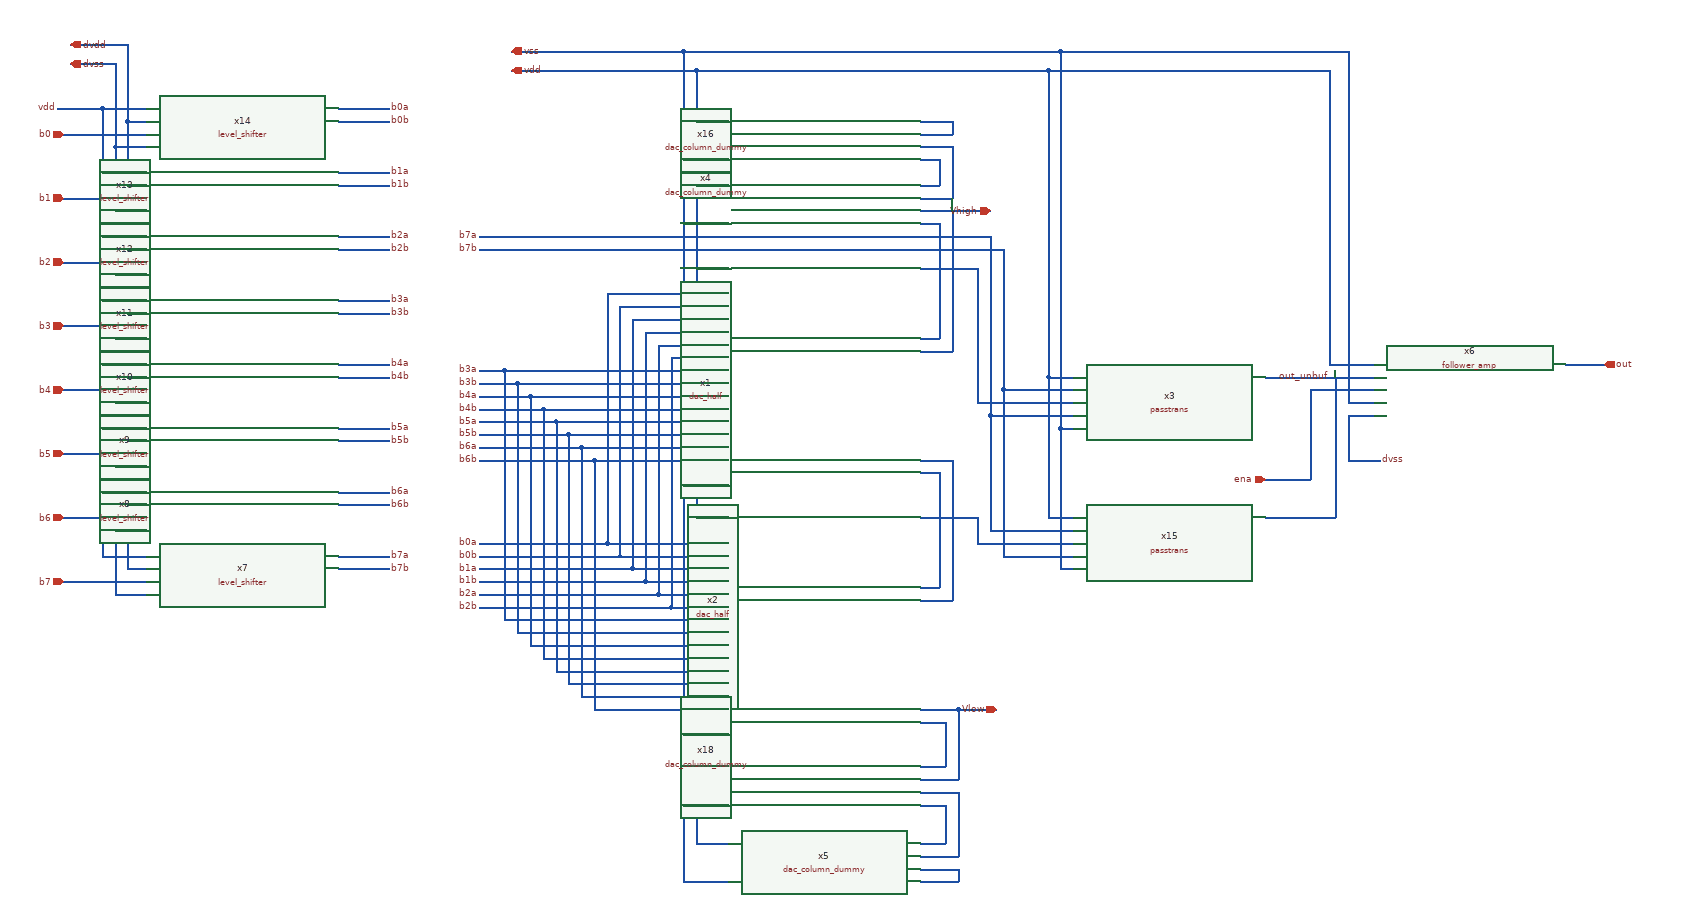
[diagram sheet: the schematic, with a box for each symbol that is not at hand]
v {xschem version=3.4.5 file_version=1.2
}
G {}
K {}
V {}
S {}
E {}
N 300 -2900 390 -2900 {
lab=#net1}
N 300 -2510 390 -2510 {
lab=#net2}
N 300 -2790 330 -2790 {
lab=#net3}
N 300 -2770 340 -2770 {
lab=Vhigh}
N 350 -2990 350 -2770 {
lab=Vhigh}
N 300 -2990 340 -2990 {
lab=Vhigh}
N 330 -2970 330 -2790 {
lab=#net3}
N 300 -2970 330 -2970 {
lab=#net3}
N 340 -2990 410 -2990 {
lab=Vhigh}
N 300 -2190 340 -2190 {
lab=#net4}
N 340 -2190 340 -2120 {
lab=#net4}
N 300 -2120 340 -2120 {
lab=#net4}
N 300 -2210 360 -2210 {
lab=Vlow}
N 360 -2210 360 -2100 {
lab=Vlow}
N 300 -2100 360 -2100 {
lab=Vlow}
N 360 -2210 420 -2210 {
lab=Vlow}
N 300 -2580 330 -2580 {
lab=#net5}
N 330 -2580 330 -2400 {
lab=#net5}
N 300 -2400 330 -2400 {
lab=#net5}
N 300 -2600 350 -2600 {
lab=#net6}
N 350 -2600 350 -2380 {
lab=#net6}
N 300 -2380 350 -2380 {
lab=#net6}
N 410 -2950 410 -2670 {
lab=b7a}
N 390 -2690 470 -2690 {
lab=#net1}
N 410 -2670 470 -2670 {
lab=b7a}
N 430 -2710 470 -2710 {
lab=b7b}
N 430 -2930 430 -2710 {
lab=b7b}
N -50 -3210 -50 -2120 {
lab=vdd}
N -340 -3240 -70 -3240 {
lab=vss}
N -70 -2560 -0 -2560 {
lab=vss}
N -70 -2170 -0 -2170 {
lab=vss}
N 470 -2710 540 -2710 {
lab=b7b}
N 470 -2690 540 -2690 {
lab=#net1}
N 470 -2670 540 -2670 {
lab=b7a}
N 520 -2650 540 -2650 {
lab=vss}
N 520 -3240 520 -2650 {
lab=vss}
N -70 -3240 520 -3240 {
lab=vss}
N -50 -3210 500 -3210 {
lab=vdd}
N 500 -3210 500 -2730 {
lab=vdd}
N 500 -2730 540 -2730 {
lab=vdd}
N -340 -3210 -50 -3210 {
lab=vdd}
N -50 -2900 -0 -2900 {
lab=vdd}
N -50 -2510 -0 -2510 {
lab=vdd}
N -90 -2370 0 -2370 {
lab=b2b}
N -110 -2390 0 -2390 {
lab=b2a}
N -130 -2410 0 -2410 {
lab=b1b}
N -150 -2430 0 -2430 {
lab=b1a}
N -170 -2450 0 -2450 {
lab=b0b}
N -190 -2470 0 -2470 {
lab=b0a}
N -90 -2760 0 -2760 {
lab=b2b}
N -110 -2780 0 -2780 {
lab=b2a}
N -130 -2800 0 -2800 {
lab=b1b}
N -150 -2820 0 -2820 {
lab=b1a}
N -170 -2840 0 -2840 {
lab=b0b}
N -190 -2860 0 -2860 {
lab=b0a}
N -390 -2950 410 -2950 {
lab=b7a}
N -390 -2930 430 -2930 {
lab=b7b}
N -210 -2600 -0 -2600 {
lab=b6b}
N -210 -2600 -210 -2210 {
lab=b6b}
N -210 -2210 -0 -2210 {
lab=b6b}
N -230 -2230 -0 -2230 {
lab=b6a}
N -230 -2620 -230 -2230 {
lab=b6a}
N -230 -2620 0 -2620 {
lab=b6a}
N -250 -2640 -0 -2640 {
lab=b5b}
N -250 -2640 -250 -2250 {
lab=b5b}
N -250 -2250 -0 -2250 {
lab=b5b}
N -270 -2660 -0 -2660 {
lab=b5a}
N -270 -2660 -270 -2270 {
lab=b5a}
N -270 -2270 -0 -2270 {
lab=b5a}
N -290 -2680 -0 -2680 {
lab=b4b}
N -290 -2680 -290 -2290 {
lab=b4b}
N -290 -2290 -0 -2290 {
lab=b4b}
N -310 -2700 -0 -2700 {
lab=b4a}
N -310 -2310 0 -2310 {
lab=b4a}
N -310 -2700 -310 -2310 {
lab=b4a}
N -330 -2330 -0 -2330 {
lab=b3b}
N -330 -2720 -330 -2330 {
lab=b3b}
N -330 -2720 -0 -2720 {
lab=b3b}
N -350 -2740 -0 -2740 {
lab=b3a}
N -350 -2350 -0 -2350 {
lab=b3a}
N -350 -2740 -350 -2350 {
lab=b3a}
N -390 -2740 -350 -2740 {
lab=b3a}
N -390 -2720 -330 -2720 {
lab=b3b}
N -390 -2700 -310 -2700 {
lab=b4a}
N -390 -2680 -290 -2680 {
lab=b4b}
N -390 -2660 -270 -2660 {
lab=b5a}
N -390 -2640 -250 -2640 {
lab=b5b}
N -390 -2620 -230 -2620 {
lab=b6a}
N -390 -2600 -210 -2600 {
lab=b6b}
N 840 -2730 1010 -2730 {
lab=out_unbuf}
N 1310 -2750 1370 -2750 {
lab=out}
N 910 -2710 1010 -2710 {
lab=ena}
N 910 -2710 910 -2570 {
lab=ena}
N 840 -2570 910 -2570 {
lab=ena}
N 520 -3240 970 -3240 {
lab=vss}
N 970 -3240 970 -2690 {
lab=vss}
N 970 -2690 1010 -2690 {
lab=vss}
N 940 -2750 1010 -2750 {
lab=vdd}
N 940 -3210 940 -2750 {
lab=vdd}
N 500 -3210 940 -3210 {
lab=vdd}
N -610 -3150 -530 -3150 {
lab=b0a}
N -610 -3130 -530 -3130 {
lab=b0b}
N -610 -3050 -530 -3050 {
lab=b1a}
N -610 -3030 -530 -3030 {
lab=b1b}
N -610 -2950 -530 -2950 {
lab=b2a}
N -610 -2930 -530 -2930 {
lab=b2b}
N -610 -2850 -530 -2850 {
lab=b3a}
N -610 -2830 -530 -2830 {
lab=b3b}
N -610 -2750 -530 -2750 {
lab=b4a}
N -610 -2730 -530 -2730 {
lab=b4b}
N -610 -2650 -530 -2650 {
lab=b5a}
N -610 -2630 -530 -2630 {
lab=b5b}
N -610 -2550 -530 -2550 {
lab=b6a}
N -610 -2530 -530 -2530 {
lab=b6b}
N -610 -2450 -530 -2450 {
lab=b7a}
N -610 -2430 -530 -2430 {
lab=b7b}
N -980 -3150 -910 -3150 {
lab=vdd}
N -980 -3150 -980 -2450 {
lab=vdd}
N -980 -2450 -910 -2450 {
lab=vdd}
N -980 -2550 -910 -2550 {
lab=vdd}
N -980 -2650 -910 -2650 {
lab=vdd}
N -980 -2750 -910 -2750 {
lab=vdd}
N -980 -2850 -910 -2850 {
lab=vdd}
N -980 -2950 -910 -2950 {
lab=vdd}
N -980 -3050 -910 -3050 {
lab=vdd}
N -960 -3090 -910 -3090 {
lab=dvss}
N -960 -3090 -960 -2390 {
lab=dvss}
N -960 -2390 -910 -2390 {
lab=dvss}
N -960 -2490 -910 -2490 {
lab=dvss}
N -960 -2590 -910 -2590 {
lab=dvss}
N -960 -2690 -910 -2690 {
lab=dvss}
N -960 -2790 -910 -2790 {
lab=dvss}
N -960 -2890 -910 -2890 {
lab=dvss}
N -960 -2990 -910 -2990 {
lab=dvss}
N -940 -3130 -910 -3130 {
lab=dvdd}
N -940 -3130 -940 -2430 {
lab=dvdd}
N -940 -2430 -910 -2430 {
lab=dvdd}
N -940 -2530 -910 -2530 {
lab=dvdd}
N -940 -2630 -910 -2630 {
lab=dvdd}
N -940 -2730 -910 -2730 {
lab=dvdd}
N -940 -2830 -910 -2830 {
lab=dvdd}
N -940 -2930 -910 -2930 {
lab=dvdd}
N -940 -3030 -910 -3030 {
lab=dvdd}
N -1040 -2410 -910 -2410 {
lab=b7}
N -1040 -2510 -910 -2510 {
lab=b6}
N -1040 -2610 -910 -2610 {
lab=b5}
N -1040 -2710 -910 -2710 {
lab=b4}
N -1040 -2810 -910 -2810 {
lab=b3}
N -1040 -2910 -910 -2910 {
lab=b2}
N -1040 -3010 -910 -3010 {
lab=b1}
N -1040 -3110 -910 -3110 {
lab=b0}
N -1050 -3150 -980 -3150 {
lab=vdd}
N -1030 -3220 -960 -3220 {
lab=dvss}
N -960 -3220 -960 -3090 {
lab=dvss}
N -940 -3250 -940 -3130 {
lab=dvdd}
N -1030 -3250 -940 -3250 {
lab=dvdd}
N 500 -2730 500 -2510 {
lab=vdd}
N 500 -2510 540 -2510 {
lab=vdd}
N 520 -2650 520 -2430 {
lab=vss}
N 520 -2430 540 -2430 {
lab=vss}
N 430 -2710 430 -2450 {
lab=b7b}
N 430 -2450 540 -2450 {
lab=b7b}
N 410 -2670 410 -2490 {
lab=b7a}
N 410 -2490 540 -2490 {
lab=b7a}
N 950 -2730 950 -2510 {
lab=out_unbuf}
N 840 -2510 950 -2510 {
lab=out_unbuf}
N 390 -2470 540 -2470 {
lab=#net2}
N 390 -2510 390 -2470 {
lab=#net2}
N 390 -2900 390 -2690 {
lab=#net1}
N 300 -2080 360 -2080 {
lab=#net7}
N 300 -2060 340 -2060 {
lab=#net8}
N 340 -2060 340 -2000 {
lab=#net8}
N 300 -2000 340 -2000 {
lab=#net8}
N 360 -2080 360 -1980 {
lab=#net7}
N 300 -1980 360 -1980 {
lab=#net7}
N 300 -1960 360 -1960 {
lab=#net9}
N 360 -1960 360 -1940 {
lab=#net9}
N 300 -1940 360 -1940 {
lab=#net9}
N 340 -2770 350 -2770 {
lab=Vhigh}
N 300 -3030 330 -3030 {
lab=#net10}
N 330 -3070 330 -3030 {
lab=#net10}
N 300 -3070 330 -3070 {
lab=#net10}
N 300 -3090 350 -3090 {
lab=#net11}
N 350 -3090 350 -3010 {
lab=#net11}
N 300 -3010 350 -3010 {
lab=#net11}
N 300 -3110 350 -3110 {
lab=#net12}
N 350 -3130 350 -3110 {
lab=#net12}
N 300 -3130 350 -3130 {
lab=#net12}
N -90 -2760 -90 -2370 {
lab=b2b}
N -110 -2780 -110 -2390 {
lab=b2a}
N -130 -2800 -130 -2410 {
lab=b1b}
N -150 -2820 -150 -2430 {
lab=b1a}
N -170 -2840 -170 -2450 {
lab=b0b}
N -190 -2860 -190 -2470 {
lab=b0a}
N -390 -2470 -190 -2470 {
lab=b0a}
N -390 -2450 -170 -2450 {
lab=b0b}
N -390 -2430 -150 -2430 {
lab=b1a}
N -390 -2410 -130 -2410 {
lab=b1b}
N -390 -2390 -110 -2390 {
lab=b2a}
N -390 -2370 -90 -2370 {
lab=b2b}
N -70 -2970 0 -2970 {
lab=vss}
N -70 -1940 -0 -1940 {
lab=vss}
N -70 -2060 -0 -2060 {
lab=vss}
N -50 -2120 -0 -2120 {
lab=vdd}
N -50 -2120 -50 -2000 {
lab=vdd}
N -50 -2000 -0 -2000 {
lab=vdd}
N -50 -3030 0 -3030 {
lab=vdd}
N -50 -3130 -0 -3130 {
lab=vdd}
N -70 -3070 -0 -3070 {
lab=vss}
N -70 -3240 -70 -1940 {
lab=vss}
N 970 -2670 1010 -2670 {
lab=dvss}
N 970 -2670 970 -2600 {
lab=dvss}
N 970 -2600 1020 -2600 {
lab=dvss}
C {dac_half.sym} 150 -2730 0 0 {name=x1}
C {dac_half.sym} 150 -2340 0 0 {name=x2}
C {passtrans.sym} 690 -2690 0 0 {name=x3}
C {devices/opin.sym} 1370 -2750 0 0 {name=p3 lab=out}
C {devices/iopin.sym} -340 -3240 0 1 {name=p4 lab=vss}
C {devices/iopin.sym} -340 -3210 0 1 {name=p5 lab=vdd}
C {devices/iopin.sym} 410 -2990 0 0 {name=p6 lab=Vhigh}
C {devices/iopin.sym} 420 -2210 0 0 {name=p7 lab=Vlow}
C {devices/lab_pin.sym} -390 -2950 0 0 {name=l7 sig_type=std_logic lab=b7a}
C {devices/lab_pin.sym} -390 -2930 0 0 {name=l8 sig_type=std_logic lab=b7b}
C {devices/lab_pin.sym} -390 -2450 0 0 {name=l10 sig_type=std_logic lab=b0b}
C {devices/lab_pin.sym} -390 -2410 0 0 {name=l12 sig_type=std_logic lab=b1b}
C {devices/lab_pin.sym} -390 -2370 0 0 {name=l14 sig_type=std_logic lab=b2b}
C {devices/lab_pin.sym} -390 -2740 0 0 {name=l15 sig_type=std_logic lab=b3a}
C {devices/lab_pin.sym} -390 -2720 0 0 {name=l16 sig_type=std_logic lab=b3b}
C {devices/lab_pin.sym} -390 -2700 0 0 {name=l17 sig_type=std_logic lab=b4a}
C {devices/lab_pin.sym} -390 -2680 0 0 {name=l18 sig_type=std_logic lab=b4b}
C {devices/lab_pin.sym} -390 -2660 0 0 {name=l19 sig_type=std_logic lab=b5a}
C {devices/lab_pin.sym} -390 -2640 0 0 {name=l20 sig_type=std_logic lab=b5b}
C {devices/lab_pin.sym} -390 -2620 0 0 {name=l21 sig_type=std_logic lab=b6a}
C {devices/lab_pin.sym} -390 -2600 0 0 {name=l22 sig_type=std_logic lab=b6b}
C {devices/ipin.sym} 840 -2570 0 0 {name=p1 lab=ena}
C {level_shifter.sym} -760 -2420 0 0 {name=x7}
C {level_shifter.sym} -760 -2520 0 0 {name=x8}
C {level_shifter.sym} -760 -2620 0 0 {name=x9}
C {level_shifter.sym} -760 -2720 0 0 {name=x10}
C {level_shifter.sym} -760 -2820 0 0 {name=x11}
C {level_shifter.sym} -760 -2920 0 0 {name=x12}
C {level_shifter.sym} -760 -3020 0 0 {name=x13}
C {level_shifter.sym} -760 -3120 0 0 {name=x14}
C {devices/lab_pin.sym} -530 -3150 0 1 {name=l23 sig_type=std_logic lab=b0a}
C {devices/lab_pin.sym} -530 -3130 0 1 {name=l24 sig_type=std_logic lab=b0b}
C {devices/lab_pin.sym} -390 -2470 0 0 {name=l9 sig_type=std_logic lab=b0a}
C {devices/lab_pin.sym} -390 -2430 0 0 {name=l11 sig_type=std_logic lab=b1a}
C {devices/lab_pin.sym} -390 -2390 0 0 {name=l13 sig_type=std_logic lab=b2a}
C {devices/lab_pin.sym} -530 -3050 0 1 {name=l25 sig_type=std_logic lab=b1a}
C {devices/lab_pin.sym} -530 -3030 0 1 {name=l26 sig_type=std_logic lab=b1b}
C {devices/lab_pin.sym} -530 -2950 0 1 {name=l27 sig_type=std_logic lab=b2a}
C {devices/lab_pin.sym} -530 -2930 0 1 {name=l28 sig_type=std_logic lab=b2b}
C {devices/lab_pin.sym} -530 -2850 0 1 {name=l29 sig_type=std_logic lab=b3a}
C {devices/lab_pin.sym} -530 -2830 0 1 {name=l30 sig_type=std_logic lab=b3b}
C {devices/lab_pin.sym} -530 -2750 0 1 {name=l31 sig_type=std_logic lab=b4a}
C {devices/lab_pin.sym} -530 -2730 0 1 {name=l32 sig_type=std_logic lab=b4b}
C {devices/lab_pin.sym} -530 -2650 0 1 {name=l33 sig_type=std_logic lab=b5a}
C {devices/lab_pin.sym} -530 -2630 0 1 {name=l34 sig_type=std_logic lab=b5b}
C {devices/lab_pin.sym} -530 -2550 0 1 {name=l35 sig_type=std_logic lab=b6a}
C {devices/lab_pin.sym} -530 -2530 0 1 {name=l36 sig_type=std_logic lab=b6b}
C {devices/lab_pin.sym} -530 -2450 0 1 {name=l37 sig_type=std_logic lab=b7a}
C {devices/lab_pin.sym} -530 -2430 0 1 {name=l38 sig_type=std_logic lab=b7b}
C {devices/ipin.sym} -1040 -3110 0 0 {name=p2 lab=b0}
C {devices/ipin.sym} -1040 -3010 0 0 {name=p8 lab=b1}
C {devices/ipin.sym} -1040 -2910 0 0 {name=p9 lab=b2}
C {devices/ipin.sym} -1040 -2810 0 0 {name=p10 lab=b3}
C {devices/ipin.sym} -1040 -2710 0 0 {name=p11 lab=b4}
C {devices/ipin.sym} -1040 -2610 0 0 {name=p12 lab=b5}
C {devices/ipin.sym} -1040 -2510 0 0 {name=p13 lab=b6}
C {devices/ipin.sym} -1040 -2410 0 0 {name=p14 lab=b7}
C {devices/lab_pin.sym} -1050 -3150 0 0 {name=l39 sig_type=std_logic lab=vdd}
C {devices/iopin.sym} -1030 -3250 0 1 {name=p15 lab=dvdd}
C {devices/iopin.sym} -1030 -3220 0 1 {name=p16 lab=dvss}
C {../dependencies/sky130_ef_ip__samplehold/xschem/follower_amp.sym} 1160 -2720 0 0 {name=x6}
C {devices/lab_pin.sym} 940 -2730 0 0 {name=l2 sig_type=std_logic lab=out_unbuf}
C {passtrans.sym} 690 -2470 0 0 {name=x15}
C {dac_column_dummy.sym} 150 -2090 0 0 {name=x18}
C {dac_column_dummy.sym} 150 -1970 0 0 {name=x5}
C {dac_column_dummy.sym} 150 -3000 0 0 {name=x4}
C {dac_column_dummy.sym} 150 -3100 0 0 {name=x16}
C {devices/lab_pin.sym} 1020 -2600 0 1 {name=p18 sig_type=std_logic lab=dvss}
